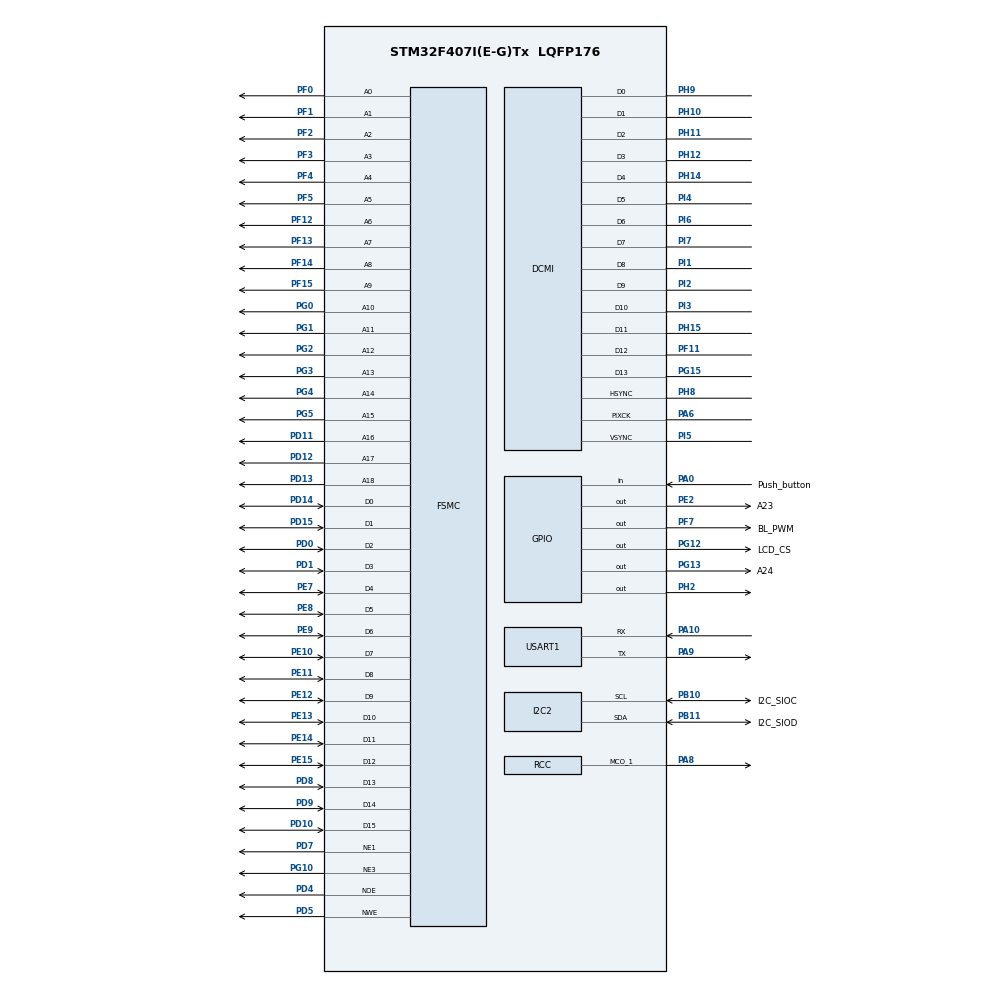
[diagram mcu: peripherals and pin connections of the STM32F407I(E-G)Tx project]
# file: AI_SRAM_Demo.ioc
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DCMI.HSPolarity=DCMI_HSPOLARITY_HIGH
DCMI.JPEGMode=DCMI_JPEG_DISABLE
DCMI.VSPolarity=DCMI_VSPOLARITY_HIGH
Dma.DCMI.0.Direction=DMA_PERIPH_TO_MEMORY
Dma.DCMI.0.FIFOMode=DMA_FIFOMODE_ENABLE
Dma.DCMI.0.FIFOThreshold=DMA_FIFO_THRESHOLD_FULL
Dma.DCMI.0.Instance=DMA2_Stream1
Dma.DCMI.0.MemBurst=DMA_MBURST_SINGLE
Dma.DCMI.0.MemDataAlignment=DMA_MDATAALIGN_WORD
Dma.DCMI.0.MemInc=DMA_MINC_ENABLE
Dma.DCMI.0.Mode=DMA_NORMAL
Dma.DCMI.0.PeriphBurst=DMA_PBURST_SINGLE
Dma.DCMI.0.PeriphDataAlignment=DMA_PDATAALIGN_WORD
Dma.DCMI.0.PeriphInc=DMA_PINC_DISABLE
Dma.DCMI.0.Priority=DMA_PRIORITY_LOW
Dma.Request0=DCMI
FSMC.AddressSetupTime1=4
FSMC.AddressSetupTime2=4
FSMC.BusTurnAroundDuration1=0
FSMC.BusTurnAroundDuration2=2
FSMC.DataSetupTime1=40
FSMC.DataSetupTime2=4
FSMC.WriteOperation2=FSMC_WRITE_OPERATION_ENABLE
Mcu.Family=STM32F4
Mcu.Name=STM32F407I(E-G)Tx
Mcu.Package=LQFP176
NVIC.DCMI_IRQn=true\:0\:0\:false\:false\:true\:true\:true
NVIC.DMA2_Stream1_IRQn=true\:0\:0\:false\:false\:true\:false\:true
NVIC.PriorityGroup=NVIC_PRIORITYGROUP_4
PA0-WKUP.GPIO_Label=Push_button
PA0-WKUP.GPIO_PuPd=GPIO_PULLUP
PA0-WKUP.Signal=GPIO_Input
PA10.Mode=Asynchronous
PA10.Signal=USART1_RX
PA6.Mode=Slave_14_bits_External_Synchro
PA6.Signal=DCMI_PIXCK
PA8.Mode=Clock-out-1
PA8.Signal=RCC_MCO_1
PA9.Mode=Asynchronous
PA9.Signal=USART1_TX
PB10.GPIO_Label=I2C_SIOC
PB10.GPIO_Speed=GPIO_SPEED_FREQ_LOW
PB10.Mode=I2C
PB10.Signal=I2C2_SCL
PB11.GPIO_Label=I2C_SIOD
PB11.Mode=I2C
PB11.Signal=I2C2_SDA
PD0.Signal=FSMC_D2_DA2
PD1.Signal=FSMC_D3_DA3
PD10.Signal=FSMC_D15_DA15
PD11.Signal=FSMC_A16_CLE
PD12.Signal=FSMC_A17_ALE
PD13.Signal=FSMC_A18
PD14.Signal=FSMC_D0_DA0
PD15.Signal=FSMC_D1_DA1
PD4.Signal=FSMC_NOE
PD5.Signal=FSMC_NWE
PD7.Mode=NorPsramChipSelect1_1
PD7.Signal=FSMC_NE1
PD8.Signal=FSMC_D13_DA13
PD9.Signal=FSMC_D14_DA14
PE0.Signal=FSMC_NBL0
PE1.Signal=FSMC_NBL1
PE10.Signal=FSMC_D7_DA7
PE11.Signal=FSMC_D8_DA8
PE12.Signal=FSMC_D9_DA9
PE13.Signal=FSMC_D10_DA10
PE14.Signal=FSMC_D11_DA11
PE15.Signal=FSMC_D12_DA12
PE2.GPIO_Label=A23
PE2.PinState=GPIO_PIN_SET
PE2.Signal=GPIO_Output
PE7.Signal=FSMC_D4_DA4
PE8.Signal=FSMC_D5_DA5
PE9.Signal=FSMC_D6_DA6
PF0.Signal=FSMC_A0
PF1.Signal=FSMC_A1
PF11.Mode=Slave_14_bits_External_Synchro
PF11.Signal=DCMI_D12
PF12.Signal=FSMC_A6
PF13.Signal=FSMC_A7
PF14.Signal=FSMC_A8
PF15.Signal=FSMC_A9
PF2.Signal=FSMC_A2
PF3.Signal=FSMC_A3
PF4.Signal=FSMC_A4
PF5.Signal=FSMC_A5
PF7.GPIO_Label=BL_PWM
PF7.PinState=GPIO_PIN_SET
PF7.Signal=GPIO_Output
PG0.Signal=FSMC_A10
PG1.Signal=FSMC_A11
PG10.Mode=NorPsramChipSelect3_2
PG10.Signal=FSMC_NE3
PG12.GPIO_Label=LCD_CS
PG12.Signal=GPIO_Output
PG13.GPIO_Label=A24
PG13.PinState=GPIO_PIN_SET
PG13.Signal=GPIO_Output
PG15.Mode=Slave_14_bits_External_Synchro
PG15.Signal=DCMI_D13
PG2.Signal=FSMC_A12
PG3.Signal=FSMC_A13
PG4.Signal=FSMC_A14
PG5.Signal=FSMC_A15
PH0-OSC_IN.Mode=HSE-External-Oscillator
PH0-OSC_IN.Signal=RCC_OSC_IN
PH1-OSC_OUT.Mode=HSE-External-Oscillator
PH1-OSC_OUT.Signal=RCC_OSC_OUT
PH10.Mode=Slave_14_bits_External_Synchro
PH10.Signal=DCMI_D1
PH11.Mode=Slave_14_bits_External_Synchro
PH11.Signal=DCMI_D2
PH12.Mode=Slave_14_bits_External_Synchro
PH12.Signal=DCMI_D3
PH14.Mode=Slave_14_bits_External_Synchro
PH14.Signal=DCMI_D4
PH15.Mode=Slave_14_bits_External_Synchro
PH15.Signal=DCMI_D11
PH2.Signal=GPIO_Output
PH8.Mode=Slave_14_bits_External_Synchro
PH8.Signal=DCMI_HSYNC
PH9.Mode=Slave_14_bits_External_Synchro
PH9.Signal=DCMI_D0
PI1.Mode=Slave_14_bits_External_Synchro
PI1.Signal=DCMI_D8
PI2.Mode=Slave_14_bits_External_Synchro
PI2.Signal=DCMI_D9
PI3.Mode=Slave_14_bits_External_Synchro
PI3.Signal=DCMI_D10
PI4.Mode=Slave_14_bits_External_Synchro
PI4.Signal=DCMI_D5
PI5.Mode=Slave_14_bits_External_Synchro
PI5.Signal=DCMI_VSYNC
PI6.Mode=Slave_14_bits_External_Synchro
PI6.Signal=DCMI_D6
PI7.Mode=Slave_14_bits_External_Synchro
PI7.Signal=DCMI_D7
ProjectManager.HeapSize=0x2000
ProjectManager.StackSize=0x6000
ProjectManager.TargetToolchain=STM32CubeIDE
RCC.AHBFreq_Value=16000000
RCC.APB1Freq_Value=16000000
RCC.APB1TimFreq_Value=16000000
RCC.APB2Freq_Value=16000000
RCC.APB2TimFreq_Value=16000000
RCC.CortexFreq_Value=16000000
RCC.HCLKFreq_Value=16000000
RCC.HSE_VALUE=8000000
RCC.HSI_VALUE=16000000
RCC.LSE_VALUE=32768
RCC.SYSCLKFreq_VALUE=16000000
RCC.VCOOutputFreq_Value=192000000
SH.FSMC_A0.0=FSMC_A0,19b-a2
SH.FSMC_A1.0=FSMC_A1,19b-a2
SH.FSMC_A10.0=FSMC_A10,19b-a2
SH.FSMC_A11.0=FSMC_A11,19b-a2
SH.FSMC_A12.0=FSMC_A12,19b-a2
SH.FSMC_A13.0=FSMC_A13,19b-a2
SH.FSMC_A14.0=FSMC_A14,19b-a2
SH.FSMC_A15.0=FSMC_A15,19b-a2
SH.FSMC_A15.1=FSMC_A15,A15_1
SH.FSMC_A16_CLE.0=FSMC_A16,19b-a2
SH.FSMC_A17_ALE.0=FSMC_A17,19b-a2
SH.FSMC_A18.0=FSMC_A18,19b-a2
SH.FSMC_A2.0=FSMC_A2,19b-a2
SH.FSMC_A3.0=FSMC_A3,19b-a2
SH.FSMC_A4.0=FSMC_A4,19b-a2
SH.FSMC_A5.0=FSMC_A5,19b-a2
SH.FSMC_A6.0=FSMC_A6,19b-a2
SH.FSMC_A7.0=FSMC_A7,19b-a2
SH.FSMC_A8.0=FSMC_A8,19b-a2
SH.FSMC_A9.0=FSMC_A9,19b-a2
SH.FSMC_D0_DA0.0=FSMC_D0,16b-d2
SH.FSMC_D0_DA0.1=FSMC_D0,16b-d1
SH.FSMC_D10_DA10.0=FSMC_D10,16b-d2
SH.FSMC_D10_DA10.1=FSMC_D10,16b-d1
SH.FSMC_D11_DA11.0=FSMC_D11,16b-d2
SH.FSMC_D11_DA11.1=FSMC_D11,16b-d1
SH.FSMC_D12_DA12.0=FSMC_D12,16b-d2
SH.FSMC_D12_DA12.1=FSMC_D12,16b-d1
SH.FSMC_D13_DA13.0=FSMC_D13,16b-d2
SH.FSMC_D13_DA13.1=FSMC_D13,16b-d1
SH.FSMC_D14_DA14.0=FSMC_D14,16b-d2
SH.FSMC_D14_DA14.1=FSMC_D14,16b-d1
SH.FSMC_D15_DA15.0=FSMC_D15,16b-d2
SH.FSMC_D15_DA15.1=FSMC_D15,16b-d1
SH.FSMC_D1_DA1.0=FSMC_D1,16b-d2
SH.FSMC_D1_DA1.1=FSMC_D1,16b-d1
SH.FSMC_D2_DA2.0=FSMC_D2,16b-d2
SH.FSMC_D2_DA2.1=FSMC_D2,16b-d1
SH.FSMC_D3_DA3.0=FSMC_D3,16b-d2
SH.FSMC_D3_DA3.1=FSMC_D3,16b-d1
SH.FSMC_D4_DA4.0=FSMC_D4,16b-d2
SH.FSMC_D4_DA4.1=FSMC_D4,16b-d1
SH.FSMC_D5_DA5.0=FSMC_D5,16b-d2
SH.FSMC_D5_DA5.1=FSMC_D5,16b-d1
SH.FSMC_D6_DA6.0=FSMC_D6,16b-d2
SH.FSMC_D6_DA6.1=FSMC_D6,16b-d1
SH.FSMC_D7_DA7.0=FSMC_D7,16b-d2
SH.FSMC_D7_DA7.1=FSMC_D7,16b-d1
SH.FSMC_D8_DA8.0=FSMC_D8,16b-d2
SH.FSMC_D8_DA8.1=FSMC_D8,16b-d1
SH.FSMC_D9_DA9.0=FSMC_D9,16b-d2
SH.FSMC_D9_DA9.1=FSMC_D9,16b-d1
SH.FSMC_NBL0.0=FSMC_NBL0
SH.FSMC_NBL1.0=FSMC_NBL1
SH.FSMC_NOE.0=FSMC_NOE,Sram2
SH.FSMC_NOE.1=FSMC_NOE,Lcd1
SH.FSMC_NWE.0=FSMC_NWE,Sram2
SH.FSMC_NWE.1=FSMC_NWE,Lcd1
STMicroelectronics.X-CUBE-AI.4.0.0.ApplicationCcArtificialOoIntelligenceJjApplication=ApplicationTemplate
STMicroelectronics.X-CUBE-AI.4.0.0.ArtificialOoIntelligenceJjApplication.cmp_version0=4.0.0
STMicroelectronics.X-CUBE-AI.4.0.0.ArtificialOoIntelligenceJjApplication.component0=Artificial Intelligence
STMicroelectronics.X-CUBE-AI.4.0.0.ArtificialOoIntelligenceJjApplication.description0=AI Application,Application Template
STMicroelectronics.X-CUBE-AI.4.0.0.ArtificialOoIntelligenceJjApplication.diagnostic0=This component should operate correctly.
STMicroelectronics.X-CUBE-AI.4.0.0.ArtificialOoIntelligenceJjApplication.documentation0=Documentation/index.html
STMicroelectronics.X-CUBE-AI.4.0.0.ArtificialOoIntelligenceJjApplication.group0=Application
STMicroelectronics.X-CUBE-AI.4.0.0.ArtificialOoIntelligenceJjApplication.paramName0=ApplicationCcArtificialOoIntelligenceJjApplication
STMicroelectronics.X-CUBE-AI.4.0.0.ArtificialOoIntelligenceJjApplication.sevirity0=none
STMicroelectronics.X-CUBE-AI.4.0.0.ArtificialOoIntelligenceJjApplication.variant0=ApplicationTemplate
STMicroelectronics.X-CUBE-AI.4.0.0.ArtificialOoIntelligenceJjApplication_bundle=Application
STMicroelectronics.X-CUBE-AI.4.0.0.ArtificialOoIntelligenceJjApplication_class=ArtificialOoIntelligence
STMicroelectronics.X-CUBE-AI.4.0.0.ArtificialOoIntelligenceJjApplication_name=X-CUBE-AI
STMicroelectronics.X-CUBE-AI.4.0.0.ArtificialOoIntelligenceJjApplication_size=1
STMicroelectronics.X-CUBE-AI.4.0.0.ArtificialOoIntelligenceJjApplication_vendor=STMicroelectronics
STMicroelectronics.X-CUBE-AI.4.0.0.ArtificialOoIntelligenceJjApplication_version=4.0.0
STMicroelectronics.X-CUBE-AI.4.0.0.ArtificialOoIntelligenceJjXAaCUBEAaAI.cmp_version0=4.0.0
STMicroelectronics.X-CUBE-AI.4.0.0.ArtificialOoIntelligenceJjXAaCUBEAaAI.cmp_version1=4.0.0
STMicroelectronics.X-CUBE-AI.4.0.0.ArtificialOoIntelligenceJjXAaCUBEAaAI.component0=Artificial Intelligence
STMicroelectronics.X-CUBE-AI.4.0.0.ArtificialOoIntelligenceJjXAaCUBEAaAI.component1=Artificial Intelligence
STMicroelectronics.X-CUBE-AI.4.0.0.ArtificialOoIntelligenceJjXAaCUBEAaAI.componentDoc0=nofile
STMicroelectronics.X-CUBE-AI.4.0.0.ArtificialOoIntelligenceJjXAaCUBEAaAI.description0=AI Core,Artificial Intelligence for STM32
STMicroelectronics.X-CUBE-AI.4.0.0.ArtificialOoIntelligenceJjXAaCUBEAaAI.description1=AI Application,Application Template
STMicroelectronics.X-CUBE-AI.4.0.0.ArtificialOoIntelligenceJjXAaCUBEAaAI.diagnostic0=This component should operate correctly.
STMicroelectronics.X-CUBE-AI.4.0.0.ArtificialOoIntelligenceJjXAaCUBEAaAI.diagnostic1=This component should operate correctly.
STMicroelectronics.X-CUBE-AI.4.0.0.ArtificialOoIntelligenceJjXAaCUBEAaAI.documentation0=Documentation/index.html
STMicroelectronics.X-CUBE-AI.4.0.0.ArtificialOoIntelligenceJjXAaCUBEAaAI.documentation1=Documentation/index.html
STMicroelectronics.X-CUBE-AI.4.0.0.ArtificialOoIntelligenceJjXAaCUBEAaAI.group0=Core
STMicroelectronics.X-CUBE-AI.4.0.0.ArtificialOoIntelligenceJjXAaCUBEAaAI.group1=Application
STMicroelectronics.X-CUBE-AI.4.0.0.ArtificialOoIntelligenceJjXAaCUBEAaAI.paramName0=XAaCUBEAaAICcArtificialOoIntelligenceJjCore
STMicroelectronics.X-CUBE-AI.4.0.0.ArtificialOoIntelligenceJjXAaCUBEAaAI.paramName1=ApplicationCcArtificialOoIntelligenceJjApplication
STMicroelectronics.X-CUBE-AI.4.0.0.ArtificialOoIntelligenceJjXAaCUBEAaAI.sevirity0=none
STMicroelectronics.X-CUBE-AI.4.0.0.ArtificialOoIntelligenceJjXAaCUBEAaAI.sevirity1=none
STMicroelectronics.X-CUBE-AI.4.0.0.ArtificialOoIntelligenceJjXAaCUBEAaAI.variant1=ApplicationTemplate
STMicroelectronics.X-CUBE-AI.4.0.0.ArtificialOoIntelligenceJjXAaCUBEAaAI_bundle=X-CUBE-AI
STMicroelectronics.X-CUBE-AI.4.0.0.ArtificialOoIntelligenceJjXAaCUBEAaAI_class=ArtificialOoIntelligence
STMicroelectronics.X-CUBE-AI.4.0.0.ArtificialOoIntelligenceJjXAaCUBEAaAI_name=X-CUBE-AI
STMicroelectronics.X-CUBE-AI.4.0.0.ArtificialOoIntelligenceJjXAaCUBEAaAI_size=2
STMicroelectronics.X-CUBE-AI.4.0.0.ArtificialOoIntelligenceJjXAaCUBEAaAI_vendor=STMicroelectronics
STMicroelectronics.X-CUBE-AI.4.0.0.ArtificialOoIntelligenceJjXAaCUBEAaAI_version=4.0.0
STMicroelectronics.X-CUBE-AI.4.0.0.LatestDirectoryUsed-f4eb9759ff1ecc597da64b09d56d9be5613efd7c4be0cd18e6a59839232a18bd=C\:\\Users\\Prakashs\\Documents\\Work\\Code_Samples\\AIDemo\\working h5
STMicroelectronics.X-CUBE-AI.4.0.0.ModelActualCompression-f4eb9759ff1ecc597da64b09d56d9be5613efd7c4be0cd18e6a59839232a18bd=0.0
STMicroelectronics.X-CUBE-AI.4.0.0.ModelCompression-f4eb9759ff1ecc597da64b09d56d9be5613efd7c4be0cd18e6a59839232a18bd=1
STMicroelectronics.X-CUBE-AI.4.0.0.ModelFlashOccupation-f4eb9759ff1ecc597da64b09d56d9be5613efd7c4be0cd18e6a59839232a18bd=407080
STMicroelectronics.X-CUBE-AI.4.0.0.ModelHashList=f4eb9759ff1ecc597da64b09d56d9be5613efd7c4be0cd18e6a59839232a18bd
STMicroelectronics.X-CUBE-AI.4.0.0.ModelKind-f4eb9759ff1ecc597da64b09d56d9be5613efd7c4be0cd18e6a59839232a18bd=KERAS
STMicroelectronics.X-CUBE-AI.4.0.0.ModelMacc-f4eb9759ff1ecc597da64b09d56d9be5613efd7c4be0cd18e6a59839232a18bd=101910
STMicroelectronics.X-CUBE-AI.4.0.0.ModelName-f4eb9759ff1ecc597da64b09d56d9be5613efd7c4be0cd18e6a59839232a18bd=imageclassify
STMicroelectronics.X-CUBE-AI.4.0.0.ModelNameList=imageclassify
STMicroelectronics.X-CUBE-AI.4.0.0.ModelRamOccupation-f4eb9759ff1ecc597da64b09d56d9be5613efd7c4be0cd18e6a59839232a18bd=552
STMicroelectronics.X-CUBE-AI.4.0.0.ModelStructureFile-f4eb9759ff1ecc597da64b09d56d9be5613efd7c4be0cd18e6a59839232a18bd=C\:\\Users\\Prakashs\\Documents\\Work\\Code_Samples\\AIDemo\\working h5\\model_weights.h5
STMicroelectronics.X-CUBE-AI.4.0.0.ModelType-f4eb9759ff1ecc597da64b09d56d9be5613efd7c4be0cd18e6a59839232a18bd=Model and Topology
STMicroelectronics.X-CUBE-AI.4.0.0.ModelWeightFile-f4eb9759ff1ecc597da64b09d56d9be5613efd7c4be0cd18e6a59839232a18bd=C\:\\Users\\Prakashs\\Documents\\Work\\Code_Samples\\AIDemo\\working h5\\model_architecture.json
STMicroelectronics.X-CUBE-AI.4.0.0.XAaCUBEAaAICcArtificialOoIntelligenceJjCore=true
STMicroelectronics.X-CUBE-AI.4.0.0_ArtificialOoIntelligenceJjApplication_RteComponent0=\#define AI_ApplicationTemplate
STMicroelectronics.X-CUBE-AI.4.0.0_ArtificialOoIntelligenceJjApplication_RteComponentsize=1
STMicroelectronics.X-CUBE-AI.4.0.0_ArtificialOoIntelligenceJjXAaCUBEAaAI_RteComponentsize=0
STMicroelectronics.X-CUBE-AI.4.0.0_MwName0=X-CUBE-AI
STMicroelectronics.X-CUBE-AI.4.0.0_MwName1=Application
STMicroelectronics.X-CUBE-AI.4.0.0_NumberOfMw=2
STMicroelectronics.X-CUBE-AI.4.0.0_description=Artificial Intelligence
STMicroelectronics.X-CUBE-AI.4.0.0_license=SLA0048.txt
USART1.VirtualMode=VM_ASYNC
VP_CRC_VS_CRC.Mode=CRC_Activate
VP_STMicroelectronics.X-CUBE-AI_VS_ArtificialOoIntelligenceJjApplication_4.0.0.Mode=ArtificialOoIntelligenceJjApplication
VP_STMicroelectronics.X-CUBE-AI_VS_ArtificialOoIntelligenceJjXAaCUBEAaAI_4.0.0.Mode=ArtificialOoIntelligenceJjXAaCUBEAaAI
board=custom

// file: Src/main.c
/* USER CODE BEGIN Header */
/**
  ******************************************************************************
  * @file           : main.c
  * @brief          : Main program body
  ******************************************************************************
  * @attention
  *
  * <h2><center>&copy; Copyright (c) 2019 STMicroelectronics.
  * All rights reserved.</center></h2>
  *
  * This software component is licensed by ST under BSD 3-Clause license,
  * the "License"; You may not use this file except in compliance with the
  * License. You may obtain a copy of the License at:
  *                        opensource.org/licenses/BSD-3-Clause
  *
  ******************************************************************************
  */
/* USER CODE END Header */

#include "main.h"
#include "app_x-cube-ai.h"

/* USER CODE BEGIN Includes */
#include "stm32_lcd_bsp.h"
#include "dcmi_ov9655.h"
#include "inputImage.h"
#ifdef __GNUC__
  /* With GCC/RAISONANCE, small printf (option LD Linker->Libraries->Small printf
     set to 'Yes') calls __io_putchar() */
  #define PUTCHAR_PROTOTYPE int __io_putchar(int ch)
#else
  #define PUTCHAR_PROTOTYPE int fputc(int ch, FILE *f)
#endif /* __GNUC__ */
/* USER CODE END Includes */

CRC_HandleTypeDef hcrc;

DCMI_HandleTypeDef hdcmi;
DMA_HandleTypeDef hdma_dcmi;

I2C_HandleTypeDef hi2c2;

UART_HandleTypeDef huart1;

SRAM_HandleTypeDef hsram1;
SRAM_HandleTypeDef hsram2;

/* USER CODE BEGIN PV */
#define XSIZE                          320
#define YSIZE                          240
#define BPP								2
#define XPos							0
#define YPos							0
#define BUFFER_LEN                     0x9600 //320*240*2/4 (Number of words)
#define DISPLAY_BUFFER_LEN			   XSIZE
#define SRAM_BANK_ADDR                 ((uint32_t)0x68000000)

uint32_t SRAM_Addr = SRAM_BANK_ADDR;
uint16_t camera_bufferDisplay[DISPLAY_BUFFER_LEN];
uint32_t SRAM_Jump_Addr = 0x0280;
uint16_t resize_160[160*120];
uint8_t resizedImage[28*28];
uint8_t grayscale[160*120];
GPIO_PinState pushBtn;
int32_t y_offset = -5;    /* y_offset is set by user */
int8_t FrameXferCplt = 0;
int8_t LineXferCplt = 0;
uint16_t LineCounter = 0;
uint8_t restart=0;
/* USER CODE END PV */

void SystemClock_Config(void);
static void MX_GPIO_Init(void);
static void MX_DMA_Init(void);
static void MX_CRC_Init(void);
static void MX_DCMI_Init(void);
static void MX_FSMC_Init(void);
static void MX_I2C2_Init(void);
static void MX_USART1_UART_Init(void);
/* USER CODE BEGIN PFP */
void convert_Grayscale(uint16_t* buffer);
void convert_8Bit_Grayscale(uint16_t* buffer);
void resizePixels(uint16_t* pixels,uint16_t w1,uint16_t h1,uint16_t w2,uint16_t h2);
void ImageResize(uint8_t *srcImage, uint32_t srcW, uint32_t srcH,
                 uint32_t pixelSize, uint32_t roiX, uint32_t roiY,
                 uint32_t roiW, uint32_t roiH,  uint8_t *dstImage,
                 uint32_t dstW, uint32_t dstH);
void RGB24_to_Float_Asym(void *pSrc, void *pDst, uint32_t pixels);
/* USER CODE END PFP */

int main(void)
{
  /* USER CODE BEGIN 1 */
	OV9655_IDTypeDef OV9655ID;
  /* USER CODE END 1 */

  /* MCU Configuration--------------------------------------------------------*/

  /* Reset of all peripherals, Initializes the Flash interface and the Systick. */
  HAL_Init();

  /* Configure the system clock */
  SystemClock_Config();

  /* Initialize all configured peripherals */
  MX_GPIO_Init();
  MX_DMA_Init();
  MX_CRC_Init();
  MX_DCMI_Init();
  MX_FSMC_Init();
  MX_I2C2_Init();
  MX_USART1_UART_Init();
  MX_X_CUBE_AI_Init();

  /* Infinite loop */
  /* USER CODE BEGIN WHILE */
  uint8_t ret = BSP_LCD_Init();
  if(ret==0x00)
  {
	   BSP_LCD_Clear(LCD_COLOR_WHITE);
  }

   printf("Demo Start\r\n");
   printf("OV9655 Init: ");
   if(DCMI_OV9655Config() == 0)
   {
     printf("OK\r\n");
   }
   else
   {
     printf("failed\r\n");
   }

	  BSP_LCD_Clear(LCD_COLOR_WHITE);
	  BSP_LCD_SetTextColor(LCD_COLOR_BLACK);
	  //BSP_LCD_DisplayStringAt(0, 100, displayMsg, CENTER_MODE);
	  HAL_DCMI_Start_DMA(&hdcmi, DCMI_MODE_CONTINUOUS, (uint32_t)camera_bufferDisplay, DISPLAY_BUFFER_LEN/2);

  while (1)
  {
    /* USER CODE END WHILE */
    /* USER CODE BEGIN 3 */
	  if(LineXferCplt)
	      {
	        /* Resolution of the output image is 320 * 242, but 4 pixels in Y axis are discarded. */
	        if((LineCounter >= YSIZE + 2) && FrameXferCplt)
	        {
	          /* Set image position */
	          ili9325_SetCursor(0, YSIZE + y_offset);
	          /* Prepare to write GRAM (0x22) */
	          LCD_IO_WriteReg(LCD_REG_34);
	          FrameXferCplt = 0;
	          LineCounter = 0;
	        }
	        /* Converts uint16_t camera_buffer to uint8_t, so the actual length is BUFFER_LEN * 2 */
	        LCD_IO_WriteMultipleData((uint8_t *)camera_bufferDisplay, DISPLAY_BUFFER_LEN*2);
	        /* Converts uint16_t camera_buffer to uint32_t, so the actual length is BUFFER_LEN / 2 */
	        HAL_DCMI_Start_DMA(&hdcmi, DCMI_MODE_CONTINUOUS, (uint32_t)camera_bufferDisplay, DISPLAY_BUFFER_LEN/2);
	        LineXferCplt = 0;
	      }
	  pushBtn = HAL_GPIO_ReadPin(Push_button_GPIO_Port, Push_button_Pin);
	  if(pushBtn == GPIO_PIN_RESET)
	  {
		  HAL_DCMI_Stop(&hdcmi);
		  HAL_GPIO_WritePin(LED1_GPIO_PORT, LED_Pin_Ready, GPIO_PIN_RESET);
		  HAL_GPIO_WritePin(LED_GPIO_PORT, LED_Pin, GPIO_PIN_SET);
		  HAL_DCMI_Start_DMA(&hdcmi, DCMI_MODE_CONTINUOUS, (uint32_t)SRAM_Addr, BUFFER_LEN);
		  HAL_Delay(1000);
		  HAL_DCMI_Stop(&hdcmi);
		  HAL_GPIO_WritePin(LED_GPIO_PORT, LED_Pin_Capture, GPIO_PIN_SET);
		  BSP_LCD_Clear(LCD_COLOR_WHITE);
		  ImageResize((uint8_t*)SRAM_Addr, 320, 240, 2, 0, 0, 0, 0, (uint8_t*)resize_160, 160, 120);
		  ili9325_DrawRGBImage(0, 0, 160, 120, (uint8_t*)resize_160);
		  convert_8Bit_Grayscale(resize_160);
		  ImageResize((uint8_t*)grayscale, 160, 120, 1, 0, 0, 0, 0, (uint8_t*)resizedImage, 28, 28);
		  HAL_GPIO_WritePin(LED1_GPIO_PORT, LED_Pin_Inference, GPIO_PIN_SET);
		  MX_X_CUBE_AI_Process();
		  restart=1;
	  }
	  else if(pushBtn == GPIO_PIN_SET)
	  {
		  if(restart)
		  {
			  HAL_GPIO_WritePin(LED1_GPIO_PORT, LED_Pin_Ready, GPIO_PIN_SET);
			  HAL_GPIO_WritePin(LED_GPIO_PORT, LED_Pin, GPIO_PIN_RESET);
			  HAL_GPIO_WritePin(LED_GPIO_PORT, LED_Pin_Capture, GPIO_PIN_RESET);
			  HAL_GPIO_WritePin(LED1_GPIO_PORT, LED_Pin_Inference, GPIO_PIN_RESET);
			  restart=0;
		  }

	  }

  }
  /* USER CODE END 3 */
}

void SystemClock_Config(void)
{
	RCC_OscInitTypeDef RCC_OscInitStruct;
		  RCC_ClkInitTypeDef RCC_ClkInitStruct;

		    /**Configure the main internal regulator output voltage
		    */
		  __HAL_RCC_PWR_CLK_ENABLE();

		  __HAL_PWR_VOLTAGESCALING_CONFIG(PWR_REGULATOR_VOLTAGE_SCALE1);

		    /**Initializes the CPU, AHB and APB busses clocks
		    */
		  RCC_OscInitStruct.OscillatorType = RCC_OSCILLATORTYPE_HSI;
		  RCC_OscInitStruct.HSIState = RCC_HSI_ON;
		  RCC_OscInitStruct.HSICalibrationValue = 16;
		  RCC_OscInitStruct.PLL.PLLState = RCC_PLL_ON;
		  RCC_OscInitStruct.PLL.PLLSource = RCC_PLLSOURCE_HSI;
		  RCC_OscInitStruct.PLL.PLLM = 8;
		  RCC_OscInitStruct.PLL.PLLN = 168;
		  RCC_OscInitStruct.PLL.PLLP = RCC_PLLP_DIV2;
		  RCC_OscInitStruct.PLL.PLLQ = 4;
		  if (HAL_RCC_OscConfig(&RCC_OscInitStruct) != HAL_OK)
		  {
		    Error_Handler();
		  }

		    /**Initializes the CPU, AHB and APB busses clocks
		    */
		  RCC_ClkInitStruct.ClockType = RCC_CLOCKTYPE_HCLK|RCC_CLOCKTYPE_SYSCLK
		                              |RCC_CLOCKTYPE_PCLK1|RCC_CLOCKTYPE_PCLK2;
		  RCC_ClkInitStruct.SYSCLKSource = RCC_SYSCLKSOURCE_PLLCLK;
		  RCC_ClkInitStruct.AHBCLKDivider = RCC_SYSCLK_DIV1;
		  RCC_ClkInitStruct.APB1CLKDivider = RCC_HCLK_DIV4;
		  RCC_ClkInitStruct.APB2CLKDivider = RCC_HCLK_DIV2;

		  if (HAL_RCC_ClockConfig(&RCC_ClkInitStruct, FLASH_LATENCY_5) != HAL_OK)
		  {
		    Error_Handler();
		  }

		  HAL_RCC_MCOConfig(RCC_MCO1, RCC_MCO1SOURCE_HSI, RCC_MCODIV_1);

		    /**Configure the Systick interrupt time
		    */
		  HAL_SYSTICK_Config(HAL_RCC_GetHCLKFreq()/1000);

		    /**Configure the Systick
		    */
		  HAL_SYSTICK_CLKSourceConfig(SYSTICK_CLKSOURCE_HCLK);

		  /* SysTick_IRQn interrupt configuration */
		  HAL_NVIC_SetPriority(SysTick_IRQn, 0, 0);
}

static void MX_CRC_Init(void)
{

  hcrc.Instance = CRC;
  if (HAL_CRC_Init(&hcrc) != HAL_OK)
  {
    Error_Handler();
  }

}

static void MX_DCMI_Init(void)
{

	hdcmi.Instance = DCMI;
	  hdcmi.Init.SynchroMode = DCMI_SYNCHRO_HARDWARE;
	  hdcmi.Init.PCKPolarity = DCMI_PCKPOLARITY_FALLING;
	  hdcmi.Init.VSPolarity = DCMI_VSPOLARITY_HIGH;
	  hdcmi.Init.HSPolarity = DCMI_HSPOLARITY_HIGH;
	  hdcmi.Init.CaptureRate = DCMI_CR_ALL_FRAME;
	  hdcmi.Init.ExtendedDataMode = DCMI_EXTEND_DATA_8B;
	  hdcmi.Init.JPEGMode = DCMI_JPEG_DISABLE;
  if (HAL_DCMI_Init(&hdcmi) != HAL_OK)
  {
    Error_Handler();
  }

}

static void MX_I2C2_Init(void)
{

	hi2c2.Instance = I2C2;
	  hi2c2.Init.ClockSpeed = 100000;
	  hi2c2.Init.DutyCycle = I2C_DUTYCYCLE_2;
	  hi2c2.Init.OwnAddress1 = 0;
	  hi2c2.Init.AddressingMode = I2C_ADDRESSINGMODE_7BIT;
	  hi2c2.Init.DualAddressMode = I2C_DUALADDRESS_DISABLE;
	  hi2c2.Init.OwnAddress2 = 0;
	  hi2c2.Init.GeneralCallMode = I2C_GENERALCALL_DISABLE;
	  hi2c2.Init.NoStretchMode = I2C_NOSTRETCH_DISABLE;
  if (HAL_I2C_Init(&hi2c2) != HAL_OK)
  {
    Error_Handler();
  }

}

static void MX_USART1_UART_Init(void)
{

  huart1.Instance = USART1;
  huart1.Init.BaudRate = 115200;
  huart1.Init.WordLength = UART_WORDLENGTH_8B;
  huart1.Init.StopBits = UART_STOPBITS_1;
  huart1.Init.Parity = UART_PARITY_NONE;
  huart1.Init.Mode = UART_MODE_TX_RX;
  huart1.Init.HwFlowCtl = UART_HWCONTROL_NONE;
  huart1.Init.OverSampling = UART_OVERSAMPLING_16;
  if (HAL_UART_Init(&huart1) != HAL_OK)
  {
    Error_Handler();
  }

}

static void MX_DMA_Init(void)
{

  /* DMA controller clock enable */
  __HAL_RCC_DMA2_CLK_ENABLE();

  /* DMA interrupt init */
  /* DMA2_Stream1_IRQn interrupt configuration */
  HAL_NVIC_SetPriority(DMA2_Stream1_IRQn, 0, 0);
  HAL_NVIC_EnableIRQ(DMA2_Stream1_IRQn);

}

static void MX_GPIO_Init(void)
{
  GPIO_InitTypeDef GPIO_InitStruct = {0};

  /* GPIO Ports Clock Enable */
  __HAL_RCC_GPIOE_CLK_ENABLE();
  __HAL_RCC_GPIOF_CLK_ENABLE();
  __HAL_RCC_GPIOH_CLK_ENABLE();
  __HAL_RCC_GPIOA_CLK_ENABLE();
  __HAL_RCC_GPIOG_CLK_ENABLE();
  __HAL_RCC_GPIOB_CLK_ENABLE();
  __HAL_RCC_GPIOD_CLK_ENABLE();
  __HAL_RCC_GPIOI_CLK_ENABLE();

  /*Configure GPIO pin Output Level */
  HAL_GPIO_WritePin(A23_GPIO_Port, A23_Pin, GPIO_PIN_SET);

  /*Configure GPIO pin Output Level */
  HAL_GPIO_WritePin(BL_PWM_GPIO_Port, BL_PWM_Pin, GPIO_PIN_SET);

  /*Configure GPIO pin Output Level */
  HAL_GPIO_WritePin(GPIOH, GPIO_PIN_2, GPIO_PIN_RESET);

  /*Configure GPIO pin Output Level */
  HAL_GPIO_WritePin(LCD_CS_GPIO_Port, LCD_CS_Pin, GPIO_PIN_RESET);

  /*Configure GPIO pin Output Level */
  HAL_GPIO_WritePin(A24_GPIO_Port, A24_Pin, GPIO_PIN_SET);

  /*Configure GPIO pin Output Level */
  HAL_GPIO_WritePin(LED_GPIO_PORT, LED_Pin, GPIO_PIN_RESET);

  /*Configure GPIO pin Output Level */
  HAL_GPIO_WritePin(LED_GPIO_PORT, LED_Pin_Capture, GPIO_PIN_RESET);

  /*Configure GPIO pin Output Level */
  HAL_GPIO_WritePin(LED1_GPIO_PORT, LED_Pin_Inference, GPIO_PIN_RESET);

  /*Configure GPIO pin Output Level */
  HAL_GPIO_WritePin(LED1_GPIO_PORT, LED_Pin_Ready, GPIO_PIN_RESET);

  /*Configure GPIO pin : A23_Pin */
  GPIO_InitStruct.Pin = A23_Pin;
  GPIO_InitStruct.Mode = GPIO_MODE_OUTPUT_PP;
  GPIO_InitStruct.Pull = GPIO_NOPULL;
  GPIO_InitStruct.Speed = GPIO_SPEED_FREQ_LOW;
  HAL_GPIO_Init(A23_GPIO_Port, &GPIO_InitStruct);

  /*Configure GPIO pin : LED_Pin_Capture */
    GPIO_InitStruct.Pin = LED_Pin_Capture;
    GPIO_InitStruct.Mode = GPIO_MODE_OUTPUT_PP;
    GPIO_InitStruct.Pull = GPIO_NOPULL;
    GPIO_InitStruct.Speed = GPIO_SPEED_FREQ_LOW;
    HAL_GPIO_Init(LED_GPIO_PORT, &GPIO_InitStruct);

    /*Configure GPIO pin : LED_Pin_Inference */
      GPIO_InitStruct.Pin = LED_Pin_Inference;
      GPIO_InitStruct.Mode = GPIO_MODE_OUTPUT_PP;
      GPIO_InitStruct.Pull = GPIO_NOPULL;
      GPIO_InitStruct.Speed = GPIO_SPEED_FREQ_LOW;
      HAL_GPIO_Init(LED1_GPIO_PORT, &GPIO_InitStruct);

      /*Configure GPIO pin : LED_Pin_Ready */
            GPIO_InitStruct.Pin = LED_Pin_Ready;
            GPIO_InitStruct.Mode = GPIO_MODE_OUTPUT_PP;
            GPIO_InitStruct.Pull = GPIO_NOPULL;
            GPIO_InitStruct.Speed = GPIO_SPEED_FREQ_LOW;
            HAL_GPIO_Init(LED1_GPIO_PORT, &GPIO_InitStruct);

  /*Configure GPIO pin : BL_PWM_Pin */
  GPIO_InitStruct.Pin = BL_PWM_Pin;
  GPIO_InitStruct.Mode = GPIO_MODE_OUTPUT_PP;
  GPIO_InitStruct.Pull = GPIO_NOPULL;
  GPIO_InitStruct.Speed = GPIO_SPEED_FREQ_LOW;
  HAL_GPIO_Init(BL_PWM_GPIO_Port, &GPIO_InitStruct);

  /*Configure GPIO pin : Push_button_Pin */
  GPIO_InitStruct.Pin = Push_button_Pin;
  GPIO_InitStruct.Mode = GPIO_MODE_INPUT;
  GPIO_InitStruct.Pull = GPIO_PULLUP;
  HAL_GPIO_Init(Push_button_GPIO_Port, &GPIO_InitStruct);

  /*Configure GPIO pin : PH2 */
  GPIO_InitStruct.Pin = GPIO_PIN_2;
  GPIO_InitStruct.Mode = GPIO_MODE_OUTPUT_PP;
  GPIO_InitStruct.Pull = GPIO_NOPULL;
  GPIO_InitStruct.Speed = GPIO_SPEED_FREQ_LOW;
  HAL_GPIO_Init(GPIOH, &GPIO_InitStruct);

  /*Configure GPIO pin : PA8 */
  GPIO_InitStruct.Pin = GPIO_PIN_8;
  GPIO_InitStruct.Mode = GPIO_MODE_AF_PP;
  GPIO_InitStruct.Pull = GPIO_NOPULL;
  GPIO_InitStruct.Speed = GPIO_SPEED_FREQ_LOW;
  GPIO_InitStruct.Alternate = GPIO_AF0_MCO;
  HAL_GPIO_Init(GPIOA, &GPIO_InitStruct);

  /*Configure GPIO pins : LCD_CS_Pin A24_Pin */
  GPIO_InitStruct.Pin = LCD_CS_Pin|A24_Pin;
  GPIO_InitStruct.Mode = GPIO_MODE_OUTPUT_PP;
  GPIO_InitStruct.Pull = GPIO_NOPULL;
  GPIO_InitStruct.Speed = GPIO_SPEED_FREQ_LOW;
  HAL_GPIO_Init(GPIOG, &GPIO_InitStruct);

}

/* FSMC initialization function */
static void MX_FSMC_Init(void)
{

  FSMC_NORSRAM_TimingTypeDef Timing = {0};

  /** Perform the SRAM1 memory initialization sequence
  */
  hsram1.Instance = FSMC_NORSRAM_DEVICE;
  hsram1.Extended = FSMC_NORSRAM_EXTENDED_DEVICE;
  /* hsram1.Init */
  hsram1.Init.NSBank = FSMC_NORSRAM_BANK1;
  hsram1.Init.DataAddressMux = FSMC_DATA_ADDRESS_MUX_DISABLE;
  hsram1.Init.MemoryType = FSMC_MEMORY_TYPE_SRAM;
  hsram1.Init.MemoryDataWidth = FSMC_NORSRAM_MEM_BUS_WIDTH_16;
  hsram1.Init.BurstAccessMode = FSMC_BURST_ACCESS_MODE_DISABLE;
  hsram1.Init.WaitSignalPolarity = FSMC_WAIT_SIGNAL_POLARITY_LOW;
  hsram1.Init.WrapMode = FSMC_WRAP_MODE_DISABLE;
  hsram1.Init.WaitSignalActive = FSMC_WAIT_TIMING_BEFORE_WS;
  hsram1.Init.WriteOperation = FSMC_WRITE_OPERATION_ENABLE;
  hsram1.Init.WaitSignal = FSMC_WAIT_SIGNAL_DISABLE;
  hsram1.Init.ExtendedMode = FSMC_EXTENDED_MODE_DISABLE;
  hsram1.Init.AsynchronousWait = FSMC_ASYNCHRONOUS_WAIT_DISABLE;
  hsram1.Init.WriteBurst = FSMC_WRITE_BURST_DISABLE;
  hsram1.Init.PageSize = FSMC_PAGE_SIZE_NONE;
  /* Timing */
  Timing.AddressSetupTime = 4;
  Timing.AddressHoldTime = 15;
  Timing.DataSetupTime = 20;
  Timing.BusTurnAroundDuration = 0;
  Timing.CLKDivision = 16;
  Timing.DataLatency = 17;
  Timing.AccessMode = FSMC_ACCESS_MODE_A;
  /* ExtTiming */

  if (HAL_SRAM_Init(&hsram1, &Timing, NULL) != HAL_OK)
  {
    Error_Handler( );
  }

  /** Perform the SRAM2 memory initialization sequence
  */
  hsram2.Instance = FSMC_NORSRAM_DEVICE;
  hsram2.Extended = FSMC_NORSRAM_EXTENDED_DEVICE;
  /* hsram2.Init */
  hsram2.Init.NSBank = FSMC_NORSRAM_BANK3;
  hsram2.Init.DataAddressMux = FSMC_DATA_ADDRESS_MUX_DISABLE;
  hsram2.Init.MemoryType = FSMC_MEMORY_TYPE_SRAM;
  hsram2.Init.MemoryDataWidth = FSMC_NORSRAM_MEM_BUS_WIDTH_16;
  hsram2.Init.BurstAccessMode = FSMC_BURST_ACCESS_MODE_DISABLE;
  hsram2.Init.WaitSignalPolarity = FSMC_WAIT_SIGNAL_POLARITY_LOW;
  hsram2.Init.WrapMode = FSMC_WRAP_MODE_DISABLE;
  hsram2.Init.WaitSignalActive = FSMC_WAIT_TIMING_BEFORE_WS;
  hsram2.Init.WriteOperation = FSMC_WRITE_OPERATION_ENABLE;
  hsram2.Init.WaitSignal = FSMC_WAIT_SIGNAL_DISABLE;
  hsram2.Init.ExtendedMode = FSMC_EXTENDED_MODE_DISABLE;
  hsram2.Init.AsynchronousWait = FSMC_ASYNCHRONOUS_WAIT_DISABLE;
  hsram2.Init.WriteBurst = FSMC_WRITE_BURST_DISABLE;
  hsram2.Init.PageSize = FSMC_PAGE_SIZE_NONE;
  /* Timing */
  Timing.AddressSetupTime = 4;
  Timing.AddressHoldTime = 15;
  Timing.DataSetupTime = 20;
  Timing.BusTurnAroundDuration = 2;
  Timing.CLKDivision = 16;
  Timing.DataLatency = 17;
  Timing.AccessMode = FSMC_ACCESS_MODE_A;
  /* ExtTiming */

  if (HAL_SRAM_Init(&hsram2, &Timing, NULL) != HAL_OK)
  {
    Error_Handler( );
  }

}

/* USER CODE BEGIN 4 */
/**
  * @brief  Frame Event callback.
  * @param  None
  * @retval None
  */
void HAL_DCMI_FrameEventCallback(DCMI_HandleTypeDef *hdcmi)
{
  /* the first frame will be abnormal, discarded */
  FrameXferCplt=1;
}

void HAL_DCMI_LineEventCallback(DCMI_HandleTypeDef *hdcmi)
{
	LineCounter++;
	LineXferCplt=1;
}

void HAL_DCMI_ErrorCallback(DCMI_HandleTypeDef *hdcmi)
{
	printf("%d",hdcmi->ErrorCode);
}

// Image rescaling using interpolation
resizePixels(uint16_t* pixels,uint16_t w1,uint16_t h1,uint16_t w2,uint16_t h2) {

    uint16_t x_ratio = (uint16_t)((w1<<16)/w2) +1;
    uint16_t y_ratio = (uint16_t)((h1<<16)/h2) +1;

    uint16_t x2, y2 ;
    for (uint16_t i=0;i<h2;i++) {
        for (uint16_t j=0;j<w2;j++) {
            x2 = ((j*x_ratio)>>16) ;
            y2 = ((i*y_ratio)>>16) ;
            resizedImage[(i*w2)+j] = pixels[(y2*w1)+x2];
        }
    }
}

/**
  * @brief  Performs image (or selected Region Of Interest) resizing using bilinear interpolation
  * @param  srcImage     Pointer to source image buffer
  * @param  srcW         Source image width
  * @param  srcH         Source image height
  * @param  pixelSize    Number of bytes per pixel
  * @param  roiX         Region Of Interest x starting location
  * @param  roiY         Region Of Interest y starting location
  * @param  roiW         Region Of Interest width
  * @param  roiH         Region Of Interest height
  * @param  dstImage     Pointer to destination image buffer
  * @param  dstW         Destination image width
  * @param  dstH         Destination image height
  * @retval void         None
  */
void ImageResize(uint8_t *srcImage, uint32_t srcW, uint32_t srcH,
                 uint32_t pixelSize, uint32_t roiX, uint32_t roiY,
                 uint32_t roiW, uint32_t roiH,  uint8_t *dstImage,
                 uint32_t dstW, uint32_t dstH)
{
  int32_t srcStride;
  float widthRatio;
  float heightRatio;

  int32_t maxWidth;
  int32_t maxHeight;

  float srcX, srcY, dX1, dY1, dX2, dY2;
  int32_t dstX1, srcY1, dstX2, srcY2;

  uint8_t *tmp1, *tmp2;
  uint8_t *p1, *p2, *p3, *p4;

  int32_t offset1;
  int32_t offset2;

  srcStride = pixelSize * srcW;

  widthRatio = ((roiW ? roiW : srcW) / (float) dstW);
  heightRatio = ((roiH ? roiH : srcH) / (float) dstH);

  /* Get horizontal and vertical limits. */
  maxWidth = (roiW ? roiW : srcW) - 1;
  maxHeight = (roiH ? roiH : srcH) - 1;

  for (int32_t y = 0; y < dstH; y++)
  {
    /* Get Y from source. */
    srcY = ((float) y * heightRatio) + roiY;
    srcY1 = (int32_t) srcY;
    srcY2 = (srcY1 == maxHeight) ? srcY1 : srcY1 + 1;
    dY1 = srcY - (float) srcY1;
    dY2 = 1.0f - dY1;

    /* Calculates the pointers to the two needed lines of the source. */
    tmp1 = srcImage + srcY1 * srcStride;
    tmp2 = srcImage + srcY2 * srcStride;

    for (int32_t x = 0; x < dstW; x++)
    {
      /* Get X from source. */
      srcX = x * widthRatio + roiX;
      dstX1 = (int32_t) srcX;
      dstX2 = (dstX1 == maxWidth) ? dstX1 : dstX1 + 1;
      dX1 = srcX - /*(float32)*/dstX1;
      dX2 = 1.0f - dX1;

      /* Calculates the four points (p1,p2, p3, p4) of the source. */
      offset1 = dstX1 * pixelSize;
      offset2 = dstX2 * pixelSize;
      p1 = tmp1 + offset1;
      p2 = tmp1 + offset2;
      p3 = tmp2 + offset1;
      p4 = tmp2 + offset2;
      /* For each channel, interpolate the four points. */
      for (int32_t ch = 0; ch < pixelSize; ch++, dstImage++, p1++, p2++, p3++, p4++)
      {
        *dstImage = (uint8_t)(dY2 * (dX2 * (*p1) + dX1 * (*p2)) + dY1 * (dX2 * (*p3) + dX1 * (*p4)));
      }
    }
  }
}

// Convert to grayscale
void convert_Grayscale(uint16_t* buffer)
{
	for(int16_t i=0; i< 320; i++)
		      {
		   	   int16_t pixel = *buffer;
		   	   int16_t red = ((pixel & 0xF800)>>11);
		   	   int16_t green = (pixel & 0x07E0);
		   	   green = green>>5;
		   	   int16_t blue = (pixel & 0x001F);
		   	   int16_t grayscale = (0.2126 * red) + (0.7152 * green / 2.0) + (0.0722 * blue);
		   	   *buffer=(grayscale<<11)+(grayscale<<6)+grayscale;
		   	   buffer++;
		      }
}

// Convert to 8 bit grayscale
void convert_8Bit_Grayscale(uint16_t* buffer)
{
	for(int16_t i=0; i< 19200; i++)
		      {
		   	   uint16_t pixel = *buffer;
		   	   uint8_t red = ((pixel & 0xF800)>>11);
		   	   uint8_t green = ((pixel & 0x07E0)>>5);
		   	   uint8_t blue = (pixel & 0x001F);
		   	   grayscale[i] = (0.2126 * red) + (0.7152 * green / 2.0) + (0.0722 * blue);
		   	   buffer++;
		      }
}

/**
  * @brief  Retargets the C library printf function to the USART.
  * @param  None
  * @retval None
  */
PUTCHAR_PROTOTYPE
{
  /* write a character to the uart1 and Loop until the end of transmission */
  HAL_UART_Transmit(&huart1, (uint8_t *)&ch, 1, 0xFFFF);

  return ch;
}
/* USER CODE END 4 */

void Error_Handler(void)
{
}

/************************ (C) COPYRIGHT STMicroelectronics *****END OF FILE****/
